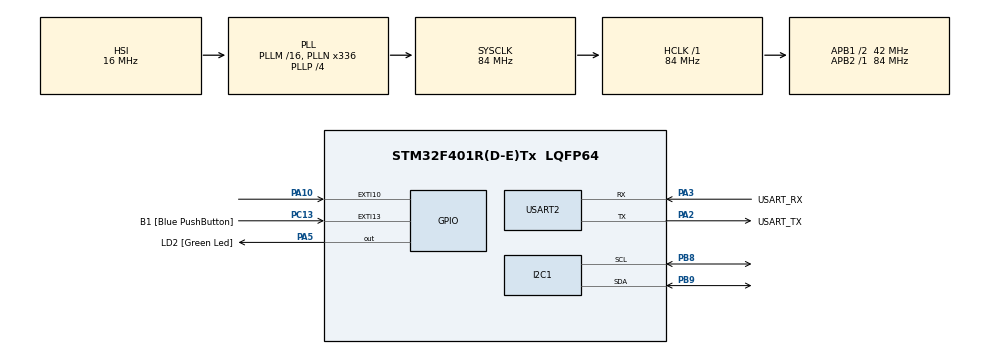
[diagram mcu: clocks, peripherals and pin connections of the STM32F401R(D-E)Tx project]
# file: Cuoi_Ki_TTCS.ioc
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Mcu.Family=STM32F4
Mcu.Name=STM32F401R(D-E)Tx
Mcu.Package=LQFP64
NVIC.EXTI15_10_IRQn=true\:0\:0\:false\:false\:true\:true\:true\:true
NVIC.PriorityGroup=NVIC_PRIORITYGROUP_0
PA10.GPIO_ModeDefaultEXTI=GPIO_MODE_IT_FALLING
PA10.GPIO_PuPd=GPIO_PULLUP
PA10.Signal=GPXTI10
PA13.GPIO_Label=TMS
PA13.Mode=Serial_Wire
PA13.Signal=SYS_JTMS-SWDIO
PA14.GPIO_Label=TCK
PA14.Mode=Serial_Wire
PA14.Signal=SYS_JTCK-SWCLK
PA2.GPIO_Label=USART_TX
PA2.GPIO_Mode=GPIO_MODE_AF_PP
PA2.GPIO_PuPd=GPIO_NOPULL
PA2.GPIO_Speed=GPIO_SPEED_FREQ_LOW
PA2.Mode=Asynchronous
PA2.Signal=USART2_TX
PA3.GPIO_Label=USART_RX
PA3.GPIO_Mode=GPIO_MODE_AF_PP
PA3.GPIO_PuPd=GPIO_NOPULL
PA3.GPIO_Speed=GPIO_SPEED_FREQ_LOW
PA3.Mode=Asynchronous
PA3.Signal=USART2_RX
PA5.GPIO_Label=LD2 [Green Led]
PA5.GPIO_Mode=GPIO_MODE_OUTPUT_PP
PA5.GPIO_PuPd=GPIO_NOPULL
PA5.GPIO_Speed=GPIO_SPEED_FREQ_LOW
PA5.Signal=GPIO_Output
PB3.GPIO_Label=SWO
PB3.Signal=SYS_JTDO-SWO
PB8.Mode=I2C
PB8.Signal=I2C1_SCL
PB9.Mode=I2C
PB9.Signal=I2C1_SDA
PC13-ANTI_TAMP.GPIO_Label=B1 [Blue PushButton]
PC13-ANTI_TAMP.GPIO_ModeDefaultEXTI=GPIO_MODE_IT_FALLING
PC13-ANTI_TAMP.GPIO_PuPd=GPIO_NOPULL
PC13-ANTI_TAMP.Signal=GPXTI13
PC14-OSC32_IN.Mode=LSE-External-Oscillator
PC14-OSC32_IN.Signal=RCC_OSC32_IN
PC15-OSC32_OUT.Mode=LSE-External-Oscillator
PC15-OSC32_OUT.Signal=RCC_OSC32_OUT
PH0\ -\ OSC_IN.Mode=HSE-External-Clock-Source
PH0\ -\ OSC_IN.Signal=RCC_OSC_IN
PH1\ -\ OSC_OUT.Mode=HSE-External-Clock-Source
PH1\ -\ OSC_OUT.Signal=RCC_OSC_OUT
ProjectManager.HeapSize=0x200
ProjectManager.StackSize=0x400
ProjectManager.TargetToolchain=STM32CubeIDE
RCC.48MHZClocksFreq_Value=48000000
RCC.AHBFreq_Value=84000000
RCC.APB1CLKDivider=RCC_HCLK_DIV2
RCC.APB1Freq_Value=42000000
RCC.APB1TimFreq_Value=84000000
RCC.APB2Freq_Value=84000000
RCC.APB2TimFreq_Value=84000000
RCC.CortexFreq_Value=84000000
RCC.HCLKFreq_Value=84000000
RCC.HSE_VALUE=8000000
RCC.HSI_VALUE=16000000
RCC.PLLN=336
RCC.PLLP=RCC_PLLP_DIV4
RCC.PLLQ=7
RCC.SYSCLKFreq_VALUE=84000000
RCC.SYSCLKSource=RCC_SYSCLKSOURCE_PLLCLK
RCC.VCOOutputFreq_Value=336000000
USART2.VirtualMode=VM_ASYNC
board=NUCLEO-F401RE

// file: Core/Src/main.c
/* USER CODE BEGIN Header */
/**
  ******************************************************************************
  * @file           : main.c
  * @brief          : Main program body
  ******************************************************************************
  * @attention
  *
  * Copyright (c) 2024 STMicroelectronics.
  * All rights reserved.
  *
  * This software is licensed under terms that can be found in the LICENSE file
  * in the root directory of this software component.
  * If no LICENSE file comes with this software, it is provided AS-IS.
  *
  ******************************************************************************
  */
/* USER CODE END Header */
#include "main.h"
#include "liquidcrystal_i2c.h"
#include "stdio.h"
#include "stdint.h"
#include "string.h"
#include "DHT.h"
#include <stdlib.h>

/* USER CODE BEGIN PD */
#define	LOW									0
#define	HIGH								1
#define BTN_PRESS							1
/* USER CODE END PD */

// khai bao led red
#define ledred_Pin GPIO_PIN_1
#define ledred_GPIO_Port GPIOA
// khai bao led green
#define ledblue_Pin GPIO_PIN_4
#define ledblue_GPIO_Port GPIOA
// khai bao led blue
#define ledgreen_Pin GPIO_PIN_0
#define ledgreen_GPIO_Port GPIOB
//L298N_in1
#define L298N_in1_Pin GPIO_PIN_5
#define L298N_in1_GPIO_Port GPIOB
// L2988N_in2
#define L298N_in2_Pin GPIO_PIN_7
#define L298N_in2_GPIO_Port GPIOB
I2C_HandleTypeDef hi2c1;

UART_HandleTypeDef huart2;

void SystemClock_Config(void);
static void MX_GPIO_Init(void);
static void MX_USART2_UART_Init(void);
static void MX_I2C1_Init(void);

void Read_DataDHT(void);
DHT_DataTypedef DHT11_Data;
float temp, humi;
int i = 0;
long last = 0;

char status[3];
uint8_t nhiet_do;
uint8_t ok = 0;
uint8_t flag = 1;
uint8_t co = 1;

// ham dieu khien ngat
void HAL_GPIO_EXTI_Callback(uint16_t GPIO_Pin)
{
	HAL_GPIO_TogglePin(L298N_in1_GPIO_Port,L298N_in1_Pin);
	HAL_GPIO_WritePin(L298N_in2_GPIO_Port,L298N_in2_Pin, LOW);
	HAL_GPIO_TogglePin(ledred_GPIO_Port,ledred_Pin);
	HAL_GPIO_TogglePin(ledgreen_GPIO_Port,ledgreen_Pin);
	HAL_GPIO_TogglePin(ledblue_GPIO_Port,ledblue_Pin);
	//HAL_GPIO_TogglePin(coi_GPIO_Port,coi_Pin);
//	for(int i = 0; i <=1; i++){

//	}
	if(ok == 0){
		ok = 1;
	}else{
		ok = 0;
	}

	if(flag==0){
		flag = 1;
	}else{
		flag = 0;
	}

	if(co==0){
			co = 1;
		}else{
			co = 0;
		}
}

int main(void)
{

  /* MCU Configuration--------------------------------------------------------*/

  /* Reset of all peripherals, Initializes the Flash interface and the Systick. */
  HAL_Init();

  /* Configure the system clock */
  SystemClock_Config();

  /* Initialize all configured peripherals */
  MX_GPIO_Init();
  MX_USART2_UART_Init();
  MX_I2C1_Init();
  HD44780_Init(2);

  /* Infinite loop */
  /* USER CODE BEGIN WHILE */
   HD44780_Clear();
   HD44780_SetCursor(2,0);
   HD44780_PrintStr("HELLO C.A.T");
   HD44780_SetCursor(1,1);
   HD44780_PrintStr("Chao_moi_nguoi");

  while (1)
  {

	  Read_DataDHT();

	  if(nhiet_do >=35 && flag == 1){
	          HAL_GPIO_WritePin(ledred_GPIO_Port,ledred_Pin, HIGH);
	          HAL_GPIO_WritePin(ledgreen_GPIO_Port,ledgreen_Pin, HIGH);
	          HAL_GPIO_WritePin(ledblue_GPIO_Port,ledblue_Pin, HIGH);
	          HAL_GPIO_WritePin(L298N_in1_GPIO_Port,L298N_in1_Pin, HIGH);
	          HAL_GPIO_WritePin(L298N_in2_GPIO_Port,L298N_in2_Pin, LOW);
	          ok = 1;
	  }else if (nhiet_do < 35 && co == 1){
	      HAL_GPIO_WritePin(ledred_GPIO_Port,ledred_Pin, LOW);
	      HAL_GPIO_WritePin(ledgreen_GPIO_Port,ledgreen_Pin, LOW);
	      HAL_GPIO_WritePin(ledblue_GPIO_Port,ledblue_Pin, LOW);
	      HAL_GPIO_WritePin(L298N_in1_GPIO_Port,L298N_in1_Pin, LOW);
	      HAL_GPIO_WritePin(L298N_in2_GPIO_Port,L298N_in2_Pin, LOW);
	      ok = 0;
	         }

    if(ok == 1){
    	status[0]='O';
    	status[1]='N';
    	status[2]=' ';

    }else if(ok == 0){
    	status[0]='O';
    	status[1]='F';
    	status[2]='F';
    }
    HD44780_SetCursor(13,0);
    HD44780_PrintStr(status);

  }

  /* USER CODE END 3 */
}

void Read_DataDHT(void){

	DHT_GetData(&DHT11_Data);
	temp = DHT11_Data.Temperature;
	humi = DHT11_Data.Humidity;

	last = HAL_GetTick();

	nhiet_do = temp;
	float T  = temp;
	float H  = humi;
	char DHT11[20];
	while(1){
		if(HAL_GetTick() - last >= 1200){

					i++;
					//in ra lcd nhiet do
					   HD44780_Clear();
					   HD44780_SetCursor(1,0);
					   HD44780_PrintStr("C.A.T");
					   HD44780_SetCursor(9,0);
					   HD44780_PrintStr("Fan:");

					   // doi so thanh ky tu
					   	gcvt(T, 2, DHT11);
					   // in nhiet do ra lcd
					   	HD44780_SetCursor(0,1);
					   	HD44780_PrintStr("TEMP: ");
					   	HD44780_SetCursor(5,1);
					   	HD44780_PrintStr(DHT11);

					   	// doi so thanh ky tu
					   	gcvt(H, 2, DHT11);
					   	// in nhiet do ra lcd
					   	HD44780_SetCursor(9,1);
					   	HD44780_PrintStr("Humi: ");
					   	HD44780_SetCursor(14,1);
					   	HD44780_PrintStr(DHT11);

					last = HAL_GetTick();
					break;
				}
	}
}

void SystemClock_Config(void)
{
  RCC_OscInitTypeDef RCC_OscInitStruct = {0};
  RCC_ClkInitTypeDef RCC_ClkInitStruct = {0};

  /** Configure the main internal regulator output voltage
  */
  __HAL_RCC_PWR_CLK_ENABLE();
  __HAL_PWR_VOLTAGESCALING_CONFIG(PWR_REGULATOR_VOLTAGE_SCALE2);

  /** Initializes the RCC Oscillators according to the specified parameters
  * in the RCC_OscInitTypeDef structure.
  */
  RCC_OscInitStruct.OscillatorType = RCC_OSCILLATORTYPE_HSI;
  RCC_OscInitStruct.HSIState = RCC_HSI_ON;
  RCC_OscInitStruct.HSICalibrationValue = RCC_HSICALIBRATION_DEFAULT;
  RCC_OscInitStruct.PLL.PLLState = RCC_PLL_ON;
  RCC_OscInitStruct.PLL.PLLSource = RCC_PLLSOURCE_HSI;
  RCC_OscInitStruct.PLL.PLLM = 16;
  RCC_OscInitStruct.PLL.PLLN = 336;
  RCC_OscInitStruct.PLL.PLLP = RCC_PLLP_DIV4;
  RCC_OscInitStruct.PLL.PLLQ = 7;
  if (HAL_RCC_OscConfig(&RCC_OscInitStruct) != HAL_OK)
  {
    Error_Handler();
  }

  /** Initializes the CPU, AHB and APB buses clocks
  */
  RCC_ClkInitStruct.ClockType = RCC_CLOCKTYPE_HCLK|RCC_CLOCKTYPE_SYSCLK
                              |RCC_CLOCKTYPE_PCLK1|RCC_CLOCKTYPE_PCLK2;
  RCC_ClkInitStruct.SYSCLKSource = RCC_SYSCLKSOURCE_PLLCLK;
  RCC_ClkInitStruct.AHBCLKDivider = RCC_SYSCLK_DIV1;
  RCC_ClkInitStruct.APB1CLKDivider = RCC_HCLK_DIV2;
  RCC_ClkInitStruct.APB2CLKDivider = RCC_HCLK_DIV1;

  if (HAL_RCC_ClockConfig(&RCC_ClkInitStruct, FLASH_LATENCY_2) != HAL_OK)
  {
    Error_Handler();
  }
}

static void MX_I2C1_Init(void)
{

  hi2c1.Instance = I2C1;
  hi2c1.Init.ClockSpeed = 100000;
  hi2c1.Init.DutyCycle = I2C_DUTYCYCLE_2;
  hi2c1.Init.OwnAddress1 = 0;
  hi2c1.Init.AddressingMode = I2C_ADDRESSINGMODE_7BIT;
  hi2c1.Init.DualAddressMode = I2C_DUALADDRESS_DISABLE;
  hi2c1.Init.OwnAddress2 = 0;
  hi2c1.Init.GeneralCallMode = I2C_GENERALCALL_DISABLE;
  hi2c1.Init.NoStretchMode = I2C_NOSTRETCH_DISABLE;
  if (HAL_I2C_Init(&hi2c1) != HAL_OK)
  {
    Error_Handler();
  }

}

static void MX_USART2_UART_Init(void)
{

  huart2.Instance = USART2;
  huart2.Init.BaudRate = 115200;
  huart2.Init.WordLength = UART_WORDLENGTH_8B;
  huart2.Init.StopBits = UART_STOPBITS_1;
  huart2.Init.Parity = UART_PARITY_NONE;
  huart2.Init.Mode = UART_MODE_TX_RX;
  huart2.Init.HwFlowCtl = UART_HWCONTROL_NONE;
  huart2.Init.OverSampling = UART_OVERSAMPLING_16;
  if (HAL_UART_Init(&huart2) != HAL_OK)
  {
    Error_Handler();
  }

}

static void MX_GPIO_Init(void)
{
  GPIO_InitTypeDef GPIO_InitStruct = {0};

  /* GPIO Ports Clock Enable */
  __HAL_RCC_GPIOC_CLK_ENABLE();
  __HAL_RCC_GPIOH_CLK_ENABLE();
  __HAL_RCC_GPIOA_CLK_ENABLE();
  __HAL_RCC_GPIOB_CLK_ENABLE();

  /*Configure GPIO pin Output Level */
  HAL_GPIO_WritePin(LD2_GPIO_Port, LD2_Pin, GPIO_PIN_RESET);

  /*Configure GPIO pin : B1_Pin */ // nt nhan user
  GPIO_InitStruct.Pin = B1_Pin;
  GPIO_InitStruct.Mode = GPIO_MODE_IT_FALLING;
  GPIO_InitStruct.Pull = GPIO_NOPULL;
  HAL_GPIO_Init(B1_GPIO_Port, &GPIO_InitStruct);

  /*Configure GPIO pin : LD2_Pin */ // led board
  GPIO_InitStruct.Pin = LD2_Pin;
  GPIO_InitStruct.Mode = GPIO_MODE_OUTPUT_PP;
  GPIO_InitStruct.Pull = GPIO_NOPULL;
  GPIO_InitStruct.Speed = GPIO_SPEED_FREQ_LOW;
  HAL_GPIO_Init(LD2_GPIO_Port, &GPIO_InitStruct);

  /*Configure GPIO pin : PA10 */ // nut nhan A10
  GPIO_InitStruct.Pin = GPIO_PIN_10;
  GPIO_InitStruct.Mode = GPIO_MODE_IT_FALLING;
  GPIO_InitStruct.Pull = GPIO_PULLUP;
  HAL_GPIO_Init(GPIOA, &GPIO_InitStruct);

  // ledred A1
    GPIO_InitStruct.Pin = ledred_Pin;
    GPIO_InitStruct.Mode = GPIO_MODE_OUTPUT_PP;
    GPIO_InitStruct.Pull = GPIO_NOPULL;
    GPIO_InitStruct.Speed = GPIO_SPEED_FREQ_MEDIUM;
    HAL_GPIO_Init(ledred_GPIO_Port, &GPIO_InitStruct);

    // ledgreen A4
   GPIO_InitStruct.Pin = ledgreen_Pin;
   GPIO_InitStruct.Mode = GPIO_MODE_OUTPUT_PP;
   GPIO_InitStruct.Pull = GPIO_NOPULL;
   GPIO_InitStruct.Speed = GPIO_SPEED_FREQ_MEDIUM;
   HAL_GPIO_Init(ledgreen_GPIO_Port, &GPIO_InitStruct);
   // ledblue A4
   GPIO_InitStruct.Pin = ledblue_Pin;
   GPIO_InitStruct.Mode = GPIO_MODE_OUTPUT_PP;
   GPIO_InitStruct.Pull = GPIO_NOPULL;
   GPIO_InitStruct.Speed = GPIO_SPEED_FREQ_MEDIUM;
   HAL_GPIO_Init(ledblue_GPIO_Port, &GPIO_InitStruct);
   // L2998N_in1
   GPIO_InitStruct.Pin = L298N_in1_Pin;
   GPIO_InitStruct.Mode = GPIO_MODE_OUTPUT_PP;
   GPIO_InitStruct.Pull = GPIO_NOPULL;
   GPIO_InitStruct.Speed = GPIO_SPEED_FREQ_MEDIUM;
   HAL_GPIO_Init(L298N_in1_GPIO_Port, &GPIO_InitStruct);
   // L28N_in2
   GPIO_InitStruct.Pin = L298N_in2_Pin;
   GPIO_InitStruct.Mode = GPIO_MODE_OUTPUT_PP;
   GPIO_InitStruct.Pull = GPIO_NOPULL;
   GPIO_InitStruct.Speed = GPIO_SPEED_FREQ_MEDIUM;
   HAL_GPIO_Init(L298N_in2_GPIO_Port, &GPIO_InitStruct);

  /* EXTI interrupt init*/
  HAL_NVIC_SetPriority(EXTI15_10_IRQn, 0, 0);
  HAL_NVIC_EnableIRQ(EXTI15_10_IRQn);

}

void Error_Handler(void)
{
  __disable_irq();
  while (1)
  {
  }
}
